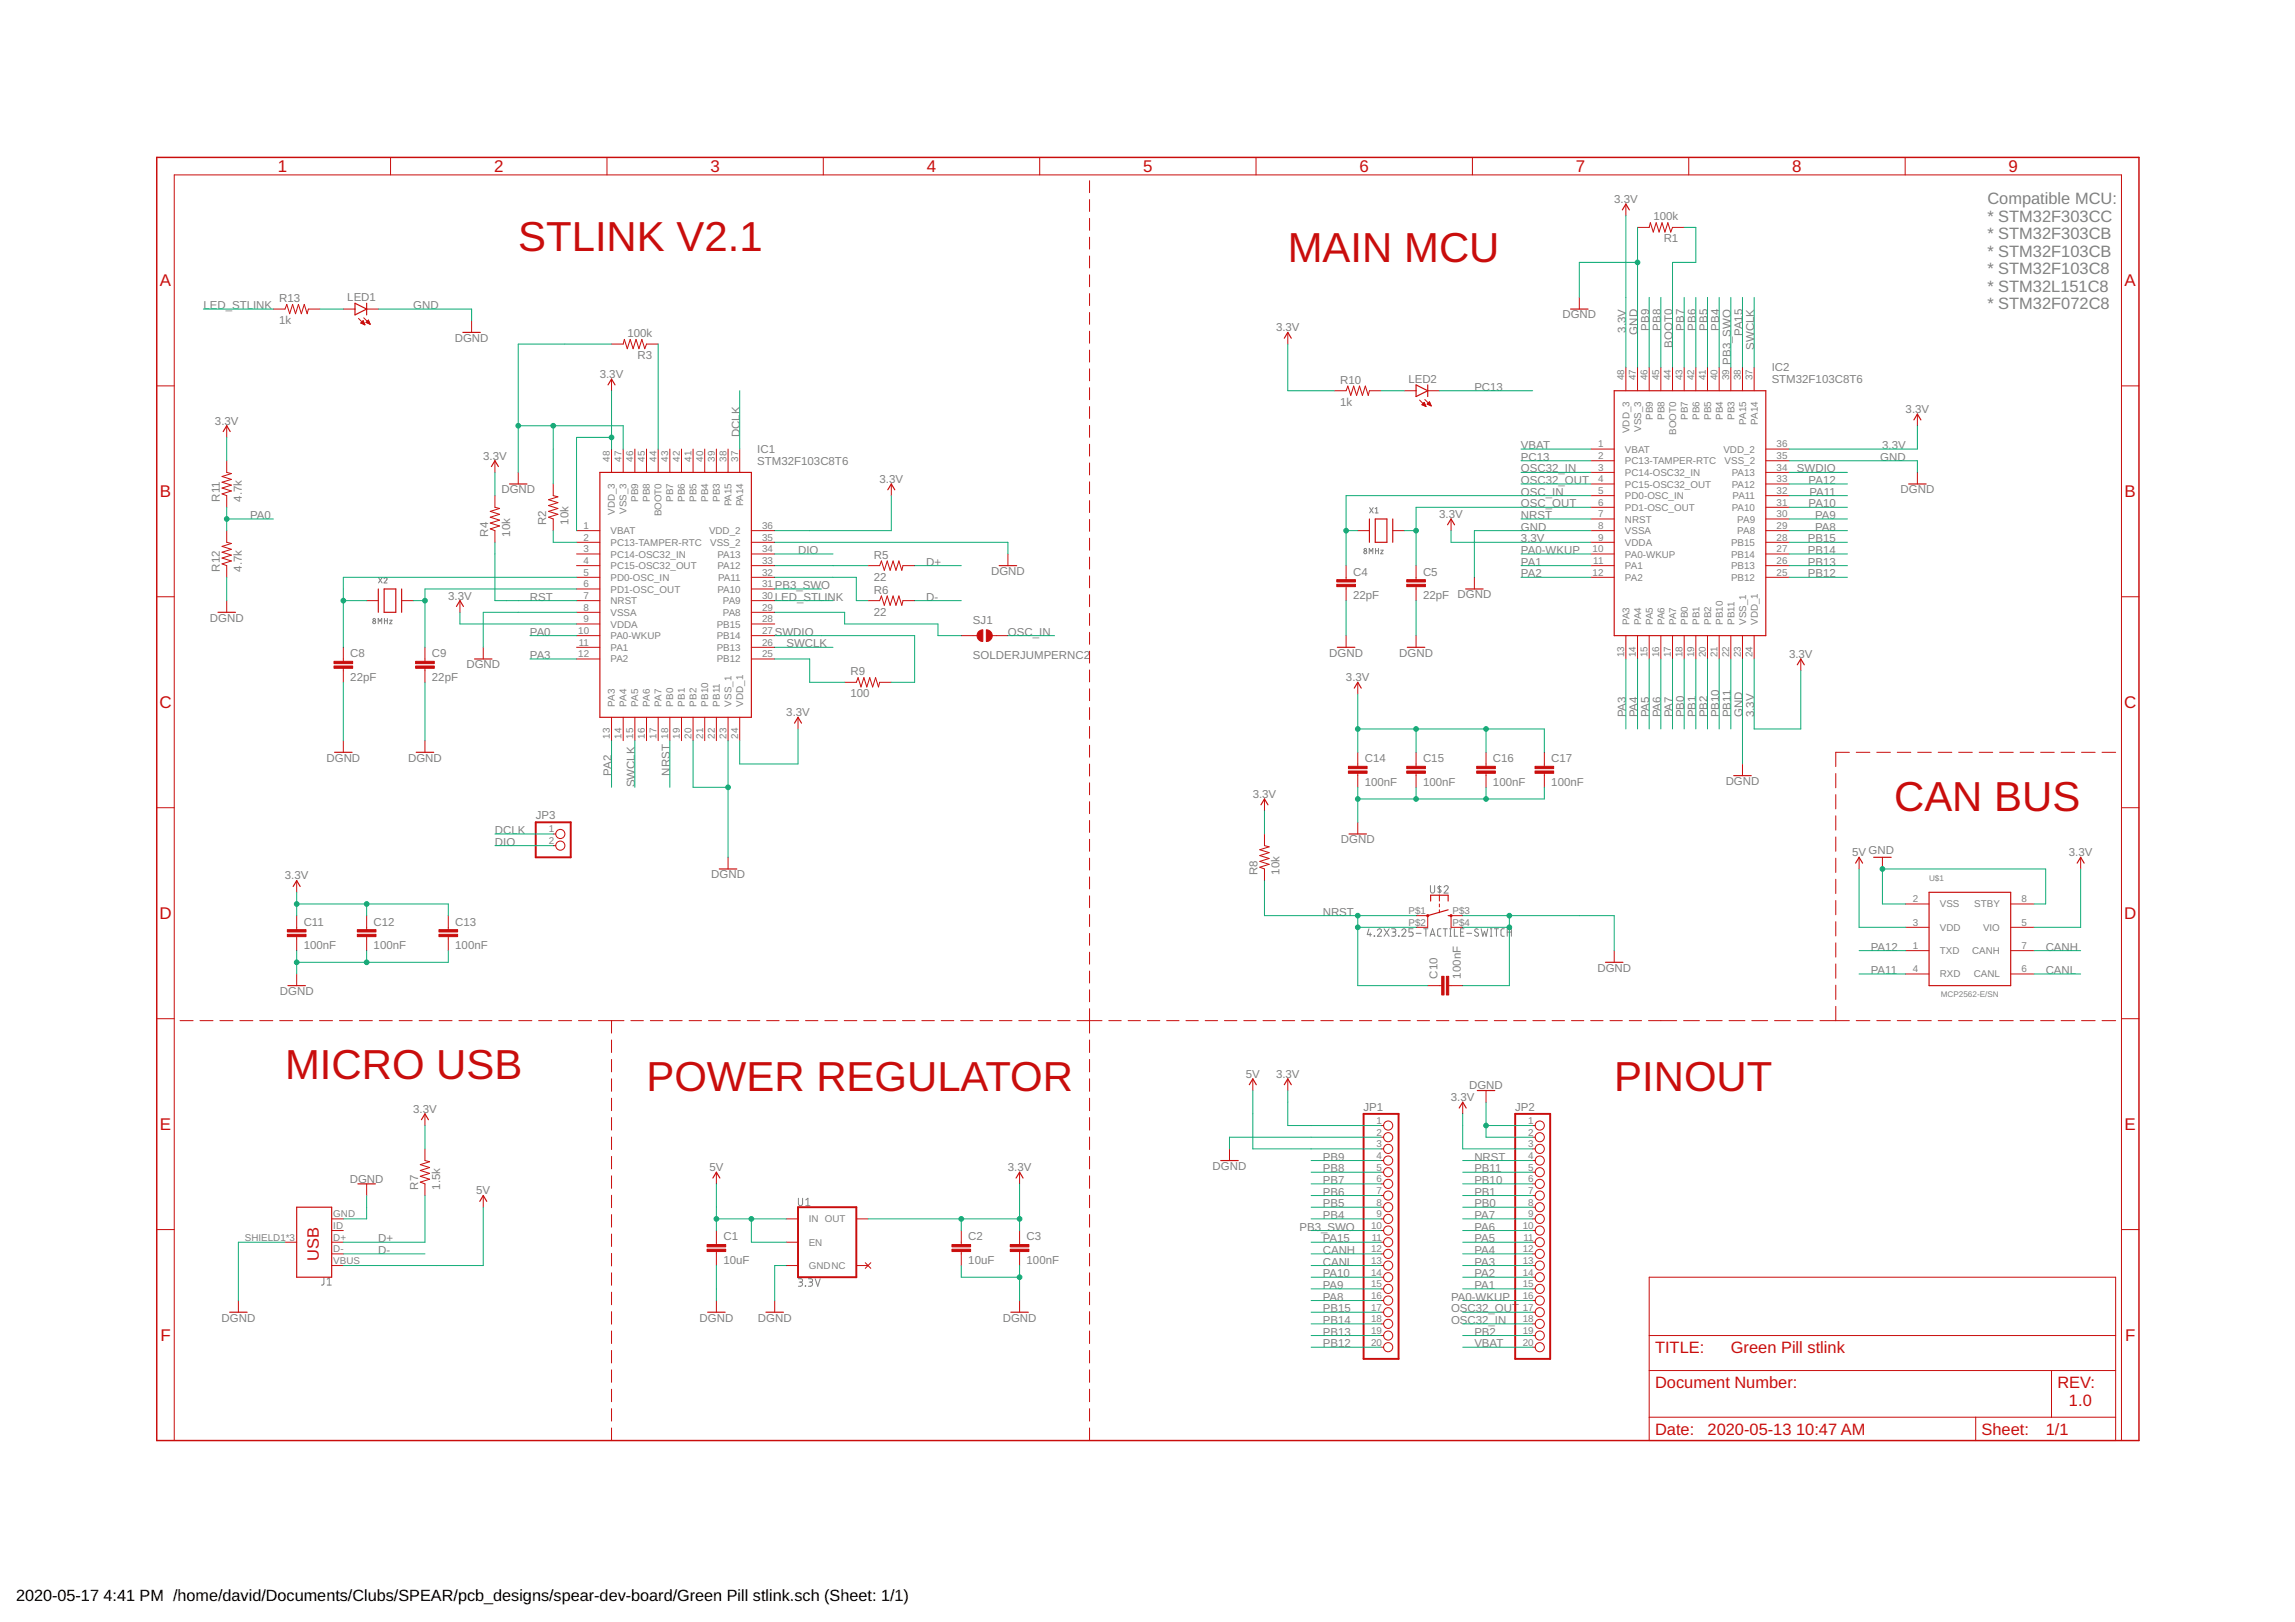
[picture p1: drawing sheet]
<svg xmlns="http://www.w3.org/2000/svg" width="500mm" height="353mm" viewBox="0 0 500 353" stroke-linecap="round" stroke-linejoin="round" font-family="sans-serif">
<defs><g id="words">
<g font-size="9.1" fill="#c90d0c">
<text x="112.9" y="54.6">STLINK V2.1</text>
<text x="280.5" y="57.1">MAIN MCU</text>
<text x="412.6" y="176.5">CAN BUS</text>
<text x="62.1" y="234.9">MICRO USB</text>
<text x="140.8" y="237.4">POWER REGULATOR</text>
<text x="351.6" y="237.4">PINOUT</text>
</g>
<g font-size="3.7" fill="#c90d0c">
<text x="60.5" y="37.5">1</text>
<text x="107.6" y="37.5">2</text>
<text x="154.8" y="37.5">3</text>
<text x="201.9" y="37.5">4</text>
<text x="249" y="37.5">5</text>
<text x="296.1" y="37.5">6</text>
<text x="343.3" y="37.5">7</text>
<text x="390.4" y="37.5">8</text>
<text x="437.5" y="37.5">9</text>
<text x="34.8" y="62.3">A</text>
<text x="462.8" y="62.3">A</text>
<text x="34.8" y="108.3">B</text>
<text x="462.8" y="108.3">B</text>
<text x="34.7" y="154.2">C</text>
<text x="462.7" y="154.2">C</text>
<text x="34.7" y="200.1">D</text>
<text x="462.7" y="200.1">D</text>
<text x="34.8" y="246">E</text>
<text x="462.8" y="246">E</text>
<text x="34.9" y="292">F</text>
<text x="462.9" y="292">F</text>
</g>
<g font-size="3.6" fill="#808080">
<text x="432.9" y="44.4">Compatible MCU:</text>
<text x="432.9" y="48.2">* STM32F303CC</text>
<text x="432.9" y="52">* STM32F303CB</text>
<text x="432.9" y="55.9">* STM32F103CB</text>
<text x="432.9" y="59.7">* STM32F103C8</text>
<text x="432.9" y="63.5">* STM32L151C8</text>
<text x="432.9" y="67.3">* STM32F072C8</text>
</g>
<g font-size="3.6" fill="#c90d0c">
<text x="69.4" y="274.5" transform="rotate(-90 69.4 274.5)">USB</text>
<text x="360.5" y="294.6">TITLE:</text>
<text x="377" y="294.6">Green Pill stlink</text>
<text x="360.5" y="302.2">Document Number:</text>
<text x="448.1" y="302.2">REV:</text>
<text x="450.7" y="306">1.0</text>
<text x="360.5" y="312.4">Date:</text>
<text x="371.9" y="312.4">2020-05-13</text>
<text x="391.2" y="312.4">10:47 AM</text>
<text x="431.6" y="312.4">Sheet:</text>
<text x="445.6" y="312.4">1/1</text>
</g>
<g font-size="3.5">
<text x="3.5" y="348.6">2020-05-17</text>
<text x="22.6" y="348.6">4:41 PM /home/david/Documents/Clubs/SPEAR/pcb_designs/spear-dev-board/Green Pill stlink.sch (Sheet: 1/1)</text>
</g>
<g font-size="2.5" fill="#808080">
<text x="351.6" y="44.2">3.3V</text>
<text x="360.2" y="48">100k</text>
<text x="362.4" y="52.8">R1</text>
<text x="60.8" y="65.8">R13</text>
<text x="75.6" y="65.5">LED1</text>
<text x="44.3" y="67.3">LED_STLINK</text>
<text x="60.8" y="70.6">1k</text>
<text x="90" y="67.3">GND</text>
<text x="340.3" y="69.3">DGND</text>
<text x="99.1" y="74.4">DGND</text>
<text x="136.7" y="73.4">100k</text>
<text x="277.9" y="72.1">3.3V</text>
<text x="354.1" y="72.4" transform="rotate(-90 354.1 72.4)">3.3V</text>
<text x="356.7" y="72.8" transform="rotate(-90 356.7 72.8)">GND</text>
<text x="359.2" y="72" transform="rotate(-90 359.2 72)">PB9</text>
<text x="361.8" y="72" transform="rotate(-90 361.8 72)">PB8</text>
<text x="364.3" y="75.8" transform="rotate(-90 364.3 75.8)">BOOT0</text>
<text x="366.8" y="72" transform="rotate(-90 366.8 72)">PB7</text>
<text x="369.4" y="72" transform="rotate(-90 369.4 72)">PB6</text>
<text x="371.9" y="72" transform="rotate(-90 371.9 72)">PB5</text>
<text x="374.5" y="72" transform="rotate(-90 374.5 72)">PB4</text>
<text x="379.5" y="73.2" transform="rotate(-90 379.5 73.2)">PA15</text>
<text x="382.1" y="76.2" transform="rotate(-90 382.1 76.2)">SWCLK</text>
<text x="130.6" y="82.3">3.3V</text>
<text x="138.9" y="78.2">R3</text>
<text x="291.9" y="83.6">R10</text>
<text x="306.8" y="83.3">LED2</text>
<text x="377" y="79.4" transform="rotate(-90 377 79.4)">PB3_SWO</text>
<text x="385.9" y="83.4">STM32F103C8T6</text>
<text x="385.9" y="80.9">IC2</text>
<text x="291.9" y="88.4">1k</text>
<text x="321.1" y="85.1">PC13</text>
<text x="415.1" y="89.9">3.3V</text>
<text x="46.8" y="92.4">3.3V</text>
<text x="161.1" y="95.2" transform="rotate(-90 161.1 95.2)">DCLK</text>
<text x="105.2" y="100">3.3V</text>
<text x="164.9" y="101.2">STM32F103C8T6</text>
<text x="164.9" y="98.6">IC1</text>
<text x="331.3" y="97.8">VBAT</text>
<text x="331.3" y="100.3">PC13</text>
<text x="409.6" y="100.3">GND</text>
<text x="410" y="97.8">3.3V</text>
<text x="109.2" y="107.4">DGND</text>
<text x="191.6" y="105.1">3.3V</text>
<text x="331.3" y="102.8">OSC32_IN</text>
<text x="331.3" y="105.4">OSC32_OUT</text>
<text x="331.3" y="107.9">OSC_IN</text>
<text x="391.4" y="102.8">SWDIO</text>
<text x="393.9" y="105.4">PA12</text>
<text x="394.1" y="107.9">PA11</text>
<text x="414" y="107.4">DGND</text>
<text x="47.9" y="109.2" transform="rotate(-90 47.9 109.2)">R11</text>
<text x="52.7" y="109.2" transform="rotate(-90 52.7 109.2)">4.7k</text>
<text x="54.5" y="113">PA0</text>
<text x="313.5" y="112.7">3.3V</text>
<text x="331.3" y="110.5">OSC_OUT</text>
<text x="331.3" y="113">NRST</text>
<text x="393.9" y="110.5">PA10</text>
<text x="395.3" y="113">PA9</text>
<text x="106.3" y="116.8" transform="rotate(-90 106.3 116.8)">R4</text>
<text x="111.1" y="116.8" transform="rotate(-90 111.1 116.8)">10k</text>
<text x="119" y="114.3" transform="rotate(-90 119 114.3)">R2</text>
<text x="123.8" y="114.3" transform="rotate(-90 123.8 114.3)">10k</text>
<text x="331.3" y="115.5">GND</text>
<text x="331.3" y="118.1">3.3V</text>
<text x="393.7" y="118.1">PB15</text>
<text x="395.3" y="115.5">PA8</text>
<text x="47.9" y="124.4" transform="rotate(-90 47.9 124.4)">R12</text>
<text x="52.7" y="124.4" transform="rotate(-90 52.7 124.4)">4.7k</text>
<text x="173.8" y="120.6">DIO</text>
<text x="190.3" y="121.7">R5</text>
<text x="201.8" y="123.2">D+</text>
<text x="215.9" y="125.2">DGND</text>
<text x="294.7" y="125.3">C4</text>
<text x="310" y="125.3">C5</text>
<text x="331.3" y="120.6">PA0-WKUP</text>
<text x="331.3" y="123.2">PA1</text>
<text x="331.3" y="125.7">PA2</text>
<text x="393.7" y="120.6">PB14</text>
<text x="393.7" y="123.2">PB13</text>
<text x="393.7" y="125.7">PB12</text>
<text x="97.6" y="130.5">3.3V</text>
<text x="115.4" y="130.8">RST</text>
<text x="168.7" y="128.2">PB3_SWO</text>
<text x="168.7" y="130.8">LED_STLINK</text>
<text x="190.3" y="126.5">22</text>
<text x="190.3" y="129.3">R6</text>
<text x="201.8" y="130.8">D-</text>
<text x="294.7" y="130.4">22pF</text>
<text x="310" y="130.4">22pF</text>
<text x="317.5" y="130.3">DGND</text>
<text x="45.7" y="135.3">DGND</text>
<text x="190.3" y="134.1">22</text>
<text x="211.9" y="135.9">SJ1</text>
<text x="76.3" y="143.1">C8</text>
<text x="94.1" y="143.1">C9</text>
<text x="115.4" y="143.5">PA3</text>
<text x="115.4" y="138.4">PA0</text>
<text x="168.7" y="138.4">SWDIO</text>
<text x="171.3" y="140.9">SWCLK</text>
<text x="211.9" y="143.5">SOLDERJUMPERNC2</text>
<text x="219.5" y="138.4">OSC_IN</text>
<text x="289.5" y="143">DGND</text>
<text x="304.8" y="143">DGND</text>
<text x="389.7" y="143.2">3.3V</text>
<text x="76.3" y="148.2">22pF</text>
<text x="94.1" y="148.2">22pF</text>
<text x="101.6" y="145.5">DGND</text>
<text x="185.3" y="147.1">R9</text>
<text x="293.2" y="148.3">3.3V</text>
<text x="171.3" y="155.9">3.3V</text>
<text x="185.3" y="151.9">100</text>
<text x="354.1" y="156.2" transform="rotate(-90 354.1 156.2)">PA3</text>
<text x="356.7" y="156.2" transform="rotate(-90 356.7 156.2)">PA4</text>
<text x="359.2" y="156.2" transform="rotate(-90 359.2 156.2)">PA5</text>
<text x="361.8" y="156.2" transform="rotate(-90 361.8 156.2)">PA6</text>
<text x="364.3" y="156.2" transform="rotate(-90 364.3 156.2)">PA7</text>
<text x="366.8" y="156.2" transform="rotate(-90 366.8 156.2)">PB0</text>
<text x="369.4" y="156.2" transform="rotate(-90 369.4 156.2)">PB1</text>
<text x="371.9" y="156.2" transform="rotate(-90 371.9 156.2)">PB2</text>
<text x="374.5" y="156.2" transform="rotate(-90 374.5 156.2)">PB10</text>
<text x="377" y="156.2" transform="rotate(-90 377 156.2)">PB11</text>
<text x="379.5" y="156.2" transform="rotate(-90 379.5 156.2)">GND</text>
<text x="382.1" y="156.2" transform="rotate(-90 382.1 156.2)">3.3V</text>
<text x="71.1" y="165.8">DGND</text>
<text x="88.9" y="165.8">DGND</text>
<text x="297.3" y="165.9">C14</text>
<text x="310" y="165.9">C15</text>
<text x="325.2" y="165.9">C16</text>
<text x="337.9" y="165.9">C17</text>
<text x="133.2" y="168.9" transform="rotate(-90 133.2 168.9)">PA2</text>
<text x="138.3" y="171.4" transform="rotate(-90 138.3 171.4)">SWCLK</text>
<text x="145.9" y="168.9" transform="rotate(-90 145.9 168.9)">NRST</text>
<text x="272.9" y="173.7">3.3V</text>
<text x="297.3" y="171">100nF</text>
<text x="310" y="171">100nF</text>
<text x="325.2" y="171">100nF</text>
<text x="337.9" y="171">100nF</text>
<text x="375.9" y="170.9">DGND</text>
<text x="116.7" y="178.4">JP3</text>
<text x="107.8" y="184.1">DIO</text>
<text x="107.8" y="181.6">DCLK</text>
<text x="292.1" y="183.6">DGND</text>
<text x="62.1" y="191.5">3.3V</text>
<text x="154.9" y="191.2">DGND</text>
<text x="273.9" y="190.5" transform="rotate(-90 273.9 190.5)">R8</text>
<text x="278.7" y="190.5" transform="rotate(-90 278.7 190.5)">10k</text>
<text x="403.4" y="186.4">5V GND</text>
<text x="450.6" y="186.4">3.3V</text>
<text x="66.1" y="201.5">C11</text>
<text x="81.4" y="201.5">C12</text>
<text x="99.2" y="201.5">C13</text>
<text x="288.1" y="199.3">NRST</text>
<text x="66.1" y="206.6">100nF</text>
<text x="81.4" y="206.6">100nF</text>
<text x="99.2" y="206.6">100nF</text>
<text x="407.5" y="207">PA12</text>
<text x="445.6" y="207">CANH</text>
<text x="313.1" y="213.1" transform="rotate(-90 313.1 213.1)">C10</text>
<text x="318.2" y="213.1" transform="rotate(-90 318.2 213.1)">100nF</text>
<text x="347.9" y="211.5">DGND</text>
<text x="407.5" y="212">PA11</text>
<text x="445.6" y="212">CANL</text>
<text x="61" y="216.6">DGND</text>
<text x="271.4" y="234.6">5V</text>
<text x="277.9" y="234.6">3.3V</text>
<text x="316" y="239.7">3.3V</text>
<text x="320" y="237.2">DGND</text>
<text x="90" y="242.3">3.3V</text>
<text x="297" y="241.9">JP1</text>
<text x="330" y="241.9">JP2</text>
<text x="76.2" y="257.5">DGND</text>
<text x="154.5" y="255">5V</text>
<text x="219.5" y="255">3.3V</text>
<text x="264.1" y="254.7">DGND</text>
<text x="288.1" y="252.7">PB9</text>
<text x="288.1" y="255.2">PB8</text>
<text x="288.1" y="257.8">PB7</text>
<text x="321.1" y="252.7">NRST</text>
<text x="321.1" y="257.8">PB10</text>
<text x="321.1" y="255.2">PB11</text>
<text x="91.1" y="259" transform="rotate(-90 91.1 259)">R7</text>
<text x="95.9" y="259" transform="rotate(-90 95.9 259)">1.5k</text>
<text x="103.7" y="260">5V</text>
<text x="288.1" y="260.3">PB6</text>
<text x="288.1" y="262.8">PB5</text>
<text x="321.1" y="262.8">PB0</text>
<text x="321.1" y="260.3">PB1</text>
<text x="283" y="267.9">PB3_SWO</text>
<text x="288.1" y="265.4">PB4</text>
<text x="321.1" y="267.9">PA6</text>
<text x="321.1" y="265.4">PA7</text>
<text x="82.4" y="270.5">D+</text>
<text x="82.4" y="273">D-</text>
<text x="157.6" y="275.1">10uF</text>
<text x="157.6" y="270.1">C1</text>
<text x="210.9" y="275.1">10uF</text>
<text x="210.9" y="270.1">C2</text>
<text x="223.6" y="275.1">100nF</text>
<text x="223.6" y="270.1">C3</text>
<text x="288.1" y="270.5">PA15</text>
<text x="288.1" y="273">CANH</text>
<text x="288.1" y="275.5">CANL</text>
<text x="321.1" y="275.5">PA3</text>
<text x="321.1" y="273">PA4</text>
<text x="321.1" y="270.5">PA5</text>
<text x="288.1" y="278.1">PA10</text>
<text x="288.1" y="280.6">PA9</text>
<text x="321.1" y="280.6">PA1</text>
<text x="321.1" y="278.1">PA2</text>
<text x="48.3" y="287.7">DGND</text>
<text x="152.4" y="287.7">DGND</text>
<text x="165.1" y="287.7">DGND</text>
<text x="218.4" y="287.7">DGND</text>
<text x="288.1" y="283.1">PA8</text>
<text x="288.1" y="285.7">PB15</text>
<text x="316.1" y="285.7">OSC32_OUT</text>
<text x="316.1" y="283.1">PA0-WKUP</text>
<text x="288.1" y="288.2">PB14</text>
<text x="288.1" y="290.8">PB13</text>
<text x="288.1" y="293.3">PB12</text>
<text x="316.1" y="288.2">OSC32_IN</text>
<text x="321.1" y="293.3">VBAT</text>
<text x="321.1" y="290.8">PB2</text>
</g>
<g font-size="2.1" fill="#808080">
<text x="353.8" y="82.7" transform="rotate(-90 353.8 82.7)">48</text>
<text x="356.3" y="82.7" transform="rotate(-90 356.3 82.7)">47</text>
<text x="358.9" y="82.7" transform="rotate(-90 358.9 82.7)">46</text>
<text x="361.4" y="82.7" transform="rotate(-90 361.4 82.7)">45</text>
<text x="364" y="82.7" transform="rotate(-90 364 82.7)">44</text>
<text x="366.5" y="82.7" transform="rotate(-90 366.5 82.7)">43</text>
<text x="369" y="82.7" transform="rotate(-90 369 82.7)">42</text>
<text x="371.6" y="82.7" transform="rotate(-90 371.6 82.7)">41</text>
<text x="374.1" y="82.7" transform="rotate(-90 374.1 82.7)">40</text>
<text x="376.7" y="82.7" transform="rotate(-90 376.7 82.7)">39</text>
<text x="379.2" y="82.7" transform="rotate(-90 379.2 82.7)">38</text>
<text x="381.7" y="82.7" transform="rotate(-90 381.7 82.7)">37</text>
<text x="354.9" y="94.3" transform="rotate(-90 354.9 94.3)">VDD_3</text>
<text x="357.5" y="94" transform="rotate(-90 357.5 94)">VSS_3</text>
<text x="360" y="91.4" transform="rotate(-90 360 91.4)">PB9</text>
<text x="362.5" y="91.4" transform="rotate(-90 362.5 91.4)">PB8</text>
<text x="365.1" y="94.6" transform="rotate(-90 365.1 94.6)">BOOT0</text>
<text x="367.6" y="91.4" transform="rotate(-90 367.6 91.4)">PB7</text>
<text x="370.2" y="91.4" transform="rotate(-90 370.2 91.4)">PB6</text>
<text x="372.7" y="91.4" transform="rotate(-90 372.7 91.4)">PB5</text>
<text x="375.2" y="91.4" transform="rotate(-90 375.2 91.4)">PB4</text>
<text x="377.8" y="91.4" transform="rotate(-90 377.8 91.4)">PB3</text>
<text x="380.3" y="92.5" transform="rotate(-90 380.3 92.5)">PA15</text>
<text x="382.8" y="92.5" transform="rotate(-90 382.8 92.5)">PA14</text>
<text x="132.8" y="100.5" transform="rotate(-90 132.8 100.5)">48</text>
<text x="135.4" y="100.5" transform="rotate(-90 135.4 100.5)">47</text>
<text x="137.9" y="100.5" transform="rotate(-90 137.9 100.5)">46</text>
<text x="140.5" y="100.5" transform="rotate(-90 140.5 100.5)">45</text>
<text x="143" y="100.5" transform="rotate(-90 143 100.5)">44</text>
<text x="145.5" y="100.5" transform="rotate(-90 145.5 100.5)">43</text>
<text x="148.1" y="100.5" transform="rotate(-90 148.1 100.5)">42</text>
<text x="150.6" y="100.5" transform="rotate(-90 150.6 100.5)">41</text>
<text x="153.2" y="100.5" transform="rotate(-90 153.2 100.5)">40</text>
<text x="155.7" y="100.5" transform="rotate(-90 155.7 100.5)">39</text>
<text x="158.2" y="100.5" transform="rotate(-90 158.2 100.5)">38</text>
<text x="160.8" y="100.5" transform="rotate(-90 160.8 100.5)">37</text>
<text x="348.1" y="97.4">1</text>
<text x="348.1" y="99.9">2</text>
<text x="353.9" y="98.5">VBAT</text>
<text x="353.9" y="101.1">PC13-TAMPER-RTC</text>
<text x="375.4" y="98.5">VDD_2</text>
<text x="375.6" y="101.1">VSS_2</text>
<text x="387" y="97.4">36</text>
<text x="387" y="99.9">35</text>
<text x="348.1" y="102.5">3</text>
<text x="348.1" y="105">4</text>
<text x="348.1" y="107.6">5</text>
<text x="353.9" y="103.6">PC14-OSC32_IN</text>
<text x="353.9" y="106.1">PC15-OSC32_OUT</text>
<text x="377.2" y="103.6">PA13</text>
<text x="377.2" y="106.1">PA12</text>
<text x="387" y="102.5">34</text>
<text x="387" y="105">33</text>
<text x="387" y="107.6">32</text>
<text x="134" y="112.1" transform="rotate(-90 134 112.1)">VDD_3</text>
<text x="136.5" y="111.8" transform="rotate(-90 136.5 111.8)">VSS_3</text>
<text x="139" y="109.2" transform="rotate(-90 139 109.2)">PB9</text>
<text x="141.6" y="109.2" transform="rotate(-90 141.6 109.2)">PB8</text>
<text x="144.1" y="112.4" transform="rotate(-90 144.1 112.4)">BOOT0</text>
<text x="146.7" y="109.2" transform="rotate(-90 146.7 109.2)">PB7</text>
<text x="149.2" y="109.2" transform="rotate(-90 149.2 109.2)">PB6</text>
<text x="151.7" y="109.2" transform="rotate(-90 151.7 109.2)">PB5</text>
<text x="154.3" y="109.2" transform="rotate(-90 154.3 109.2)">PB4</text>
<text x="156.8" y="109.2" transform="rotate(-90 156.8 109.2)">PB3</text>
<text x="159.4" y="110.3" transform="rotate(-90 159.4 110.3)">PA15</text>
<text x="161.9" y="110.3" transform="rotate(-90 161.9 110.3)">PA14</text>
<text x="348.1" y="110.1">6</text>
<text x="348.1" y="112.6">7</text>
<text x="353.9" y="108.7">PD0-OSC_IN</text>
<text x="353.9" y="111.2">PD1-OSC_OUT</text>
<text x="353.9" y="113.8">NRST</text>
<text x="377.2" y="111.2">PA10</text>
<text x="377.4" y="108.7">PA11</text>
<text x="378.4" y="113.8">PA9</text>
<text x="387" y="110.1">31</text>
<text x="387" y="112.6">30</text>
<text x="127.1" y="115.2">1</text>
<text x="127.1" y="117.7">2</text>
<text x="133" y="116.3">VBAT</text>
<text x="133" y="118.8">PC13-TAMPER-RTC</text>
<text x="154.4" y="116.3">VDD_2</text>
<text x="154.7" y="118.8">VSS_2</text>
<text x="166" y="115.2">36</text>
<text x="166" y="117.7">35</text>
<text x="348.1" y="115.2">8</text>
<text x="348.1" y="117.7">9</text>
<text x="353.9" y="116.3">VSSA</text>
<text x="353.9" y="118.8">VDDA</text>
<text x="377.1" y="118.8">PB15</text>
<text x="378.4" y="116.3">PA8</text>
<text x="387" y="115.2">29</text>
<text x="387" y="117.7">28</text>
<text x="127.1" y="120.3">3</text>
<text x="127.1" y="122.8">4</text>
<text x="127.1" y="125.3">5</text>
<text x="133" y="121.4">PC14-OSC32_IN</text>
<text x="133" y="123.9">PC15-OSC32_OUT</text>
<text x="156.3" y="121.4">PA13</text>
<text x="156.3" y="123.9">PA12</text>
<text x="166" y="120.3">34</text>
<text x="166" y="122.8">33</text>
<text x="166" y="125.3">32</text>
<text x="346.9" y="120.3">10</text>
<text x="346.9" y="125.3">12</text>
<text x="347.1" y="122.8">11</text>
<text x="353.9" y="121.4">PA0-WKUP</text>
<text x="353.9" y="123.9">PA1</text>
<text x="377.1" y="121.4">PB14</text>
<text x="377.1" y="123.9">PB13</text>
<text x="387" y="120.3">27</text>
<text x="387" y="122.8">26</text>
<text x="387" y="125.3">25</text>
<text x="127.1" y="127.9">6</text>
<text x="127.1" y="130.4">7</text>
<text x="133" y="126.5">PD0-OSC_IN</text>
<text x="133" y="129">PD1-OSC_OUT</text>
<text x="133" y="131.5">NRST</text>
<text x="156.3" y="129">PA10</text>
<text x="156.4" y="126.5">PA11</text>
<text x="157.5" y="131.5">PA9</text>
<text x="166" y="127.9">31</text>
<text x="166" y="130.4">30</text>
<text x="353.9" y="126.5">PA2</text>
<text x="377.1" y="126.5">PB12</text>
<text x="127.1" y="133">8</text>
<text x="127.1" y="135.5">9</text>
<text x="133" y="134.1">VSSA</text>
<text x="133" y="136.6">VDDA</text>
<text x="156.1" y="136.6">PB15</text>
<text x="157.5" y="134.1">PA8</text>
<text x="166" y="133">29</text>
<text x="166" y="135.5">28</text>
<text x="354.9" y="136.1" transform="rotate(-90 354.9 136.1)">PA3</text>
<text x="357.5" y="136.1" transform="rotate(-90 357.5 136.1)">PA4</text>
<text x="360" y="136.1" transform="rotate(-90 360 136.1)">PA5</text>
<text x="362.5" y="136.1" transform="rotate(-90 362.5 136.1)">PA6</text>
<text x="365.1" y="136.1" transform="rotate(-90 365.1 136.1)">PA7</text>
<text x="367.6" y="136.1" transform="rotate(-90 367.6 136.1)">PB0</text>
<text x="370.1" y="136.1" transform="rotate(-90 370.1 136.1)">PB1</text>
<text x="372.7" y="136.1" transform="rotate(-90 372.7 136.1)">PB2</text>
<text x="375.2" y="136.1" transform="rotate(-90 375.2 136.1)">PB10</text>
<text x="377.8" y="136.1" transform="rotate(-90 377.8 136.1)">PB11</text>
<text x="380.3" y="136.1" transform="rotate(-90 380.3 136.1)">VSS_1</text>
<text x="382.8" y="136.1" transform="rotate(-90 382.8 136.1)">VDD_1</text>
<text x="125.9" y="138">10</text>
<text x="125.9" y="143.1">12</text>
<text x="126.1" y="140.6">11</text>
<text x="133" y="139.2">PA0-WKUP</text>
<text x="133" y="141.7">PA1</text>
<text x="156.1" y="139.2">PB14</text>
<text x="156.1" y="141.7">PB13</text>
<text x="166" y="138">27</text>
<text x="166" y="140.6">26</text>
<text x="166" y="143.1">25</text>
<text x="353.8" y="143.1" transform="rotate(-90 353.8 143.1)">13</text>
<text x="356.3" y="143.1" transform="rotate(-90 356.3 143.1)">14</text>
<text x="358.9" y="143.1" transform="rotate(-90 358.9 143.1)">15</text>
<text x="361.4" y="143.1" transform="rotate(-90 361.4 143.1)">16</text>
<text x="364" y="143.1" transform="rotate(-90 364 143.1)">17</text>
<text x="366.5" y="143.1" transform="rotate(-90 366.5 143.1)">18</text>
<text x="369" y="143.1" transform="rotate(-90 369 143.1)">19</text>
<text x="371.6" y="143.1" transform="rotate(-90 371.6 143.1)">20</text>
<text x="374.1" y="143.1" transform="rotate(-90 374.1 143.1)">21</text>
<text x="376.7" y="143.1" transform="rotate(-90 376.7 143.1)">22</text>
<text x="379.2" y="143.1" transform="rotate(-90 379.2 143.1)">23</text>
<text x="381.7" y="143.1" transform="rotate(-90 381.7 143.1)">24</text>
<text x="133" y="144.2">PA2</text>
<text x="156.1" y="144.2">PB12</text>
<text x="134" y="153.8" transform="rotate(-90 134 153.8)">PA3</text>
<text x="136.5" y="153.8" transform="rotate(-90 136.5 153.8)">PA4</text>
<text x="139" y="153.8" transform="rotate(-90 139 153.8)">PA5</text>
<text x="141.6" y="153.8" transform="rotate(-90 141.6 153.8)">PA6</text>
<text x="144.1" y="153.8" transform="rotate(-90 144.1 153.8)">PA7</text>
<text x="146.7" y="153.8" transform="rotate(-90 146.7 153.8)">PB0</text>
<text x="149.2" y="153.8" transform="rotate(-90 149.2 153.8)">PB1</text>
<text x="151.7" y="153.8" transform="rotate(-90 151.7 153.8)">PB2</text>
<text x="154.3" y="153.8" transform="rotate(-90 154.3 153.8)">PB10</text>
<text x="156.8" y="153.8" transform="rotate(-90 156.8 153.8)">PB11</text>
<text x="159.4" y="153.8" transform="rotate(-90 159.4 153.8)">VSS_1</text>
<text x="161.9" y="153.8" transform="rotate(-90 161.9 153.8)">VDD_1</text>
<text x="132.8" y="160.9" transform="rotate(-90 132.8 160.9)">13</text>
<text x="135.4" y="160.9" transform="rotate(-90 135.4 160.9)">14</text>
<text x="137.9" y="160.9" transform="rotate(-90 137.9 160.9)">15</text>
<text x="140.5" y="160.9" transform="rotate(-90 140.5 160.9)">16</text>
<text x="143" y="160.9" transform="rotate(-90 143 160.9)">17</text>
<text x="145.5" y="160.9" transform="rotate(-90 145.5 160.9)">18</text>
<text x="148.1" y="160.9" transform="rotate(-90 148.1 160.9)">19</text>
<text x="150.6" y="160.9" transform="rotate(-90 150.6 160.9)">20</text>
<text x="153.2" y="160.9" transform="rotate(-90 153.2 160.9)">21</text>
<text x="155.7" y="160.9" transform="rotate(-90 155.7 160.9)">22</text>
<text x="158.2" y="160.9" transform="rotate(-90 158.2 160.9)">23</text>
<text x="160.8" y="160.9" transform="rotate(-90 160.8 160.9)">24</text>
<text x="119.5" y="181.2">1</text>
<text x="119.5" y="183.7">2</text>
<text x="416.7" y="196.4">2</text>
<text x="422.5" y="197.6">VSS</text>
<text x="430" y="197.6">STBY</text>
<text x="440.3" y="196.4">8</text>
<text x="306.8" y="199">P$1</text>
<text x="306.8" y="201.5">P$2</text>
<text x="316.4" y="199">P$3</text>
<text x="316.4" y="201.5">P$4</text>
<text x="416.7" y="201.5">3</text>
<text x="422.5" y="202.6">VDD</text>
<text x="431.9" y="202.6">VIO</text>
<text x="440.3" y="201.5">5</text>
<text x="416.7" y="206.6">1</text>
<text x="422.5" y="207.7">TXD</text>
<text x="429.6" y="207.7">CANH</text>
<text x="440.3" y="206.6">7</text>
<text x="416.7" y="211.7">4</text>
<text x="422.5" y="212.8">RXD</text>
<text x="429.9" y="212.8">CANL</text>
<text x="440.3" y="211.7">6</text>
<text x="299.8" y="244.7">1</text>
<text x="332.8" y="244.7">1</text>
<text x="299.8" y="247.2">2</text>
<text x="299.8" y="249.8">3</text>
<text x="332.8" y="247.2">2</text>
<text x="332.8" y="249.8">3</text>
<text x="299.8" y="252.3">4</text>
<text x="299.8" y="254.9">5</text>
<text x="299.8" y="257.4">6</text>
<text x="332.8" y="252.3">4</text>
<text x="332.8" y="254.9">5</text>
<text x="332.8" y="257.4">6</text>
<text x="299.8" y="259.9">7</text>
<text x="299.8" y="262.5">8</text>
<text x="332.8" y="259.9">7</text>
<text x="332.8" y="262.5">8</text>
<text x="72.6" y="265">GND</text>
<text x="72.6" y="267.6">ID</text>
<text x="176.2" y="266.1">IN OUT</text>
<text x="298.6" y="267.6">10</text>
<text x="299.8" y="265">9</text>
<text x="331.7" y="267.6">10</text>
<text x="332.8" y="265">9</text>
<text x="53.3" y="270.1">SHIELD1*3</text>
<text x="72.6" y="270.1">D+</text>
<text x="72.6" y="272.6">D-</text>
<text x="72.6" y="275.2">VBUS</text>
<text x="176.2" y="271.2">EN</text>
<text x="298.6" y="272.6">12</text>
<text x="298.6" y="275.2">13</text>
<text x="298.8" y="270.1">11</text>
<text x="331.7" y="272.6">12</text>
<text x="331.7" y="275.2">13</text>
<text x="331.8" y="270.1">11</text>
<text x="176.2" y="276.3">GNDNC</text>
<text x="298.6" y="277.7">14</text>
<text x="298.6" y="280.3">15</text>
<text x="331.7" y="277.7">14</text>
<text x="331.7" y="280.3">15</text>
<text x="298.6" y="282.8">16</text>
<text x="298.6" y="285.3">17</text>
<text x="298.6" y="287.9">18</text>
<text x="331.7" y="282.8">16</text>
<text x="331.7" y="285.3">17</text>
<text x="331.7" y="287.9">18</text>
<text x="298.6" y="290.4">19</text>
<text x="298.6" y="293">20</text>
<text x="331.7" y="290.4">19</text>
<text x="331.7" y="293">20</text>
</g>
<g font-size="1.8" fill="#808080">
<text x="420.2" y="191.7">U$1</text>
<text x="422.7" y="217.1">MCP2562-E/SN</text>
</g>
</g></defs>
<g fill="none" stroke="#808080" stroke-width=".22">
<path d="M298.3 110.5l.8 1.2M299.1 110.5l-.8 1.2M299.5 110.8l.4-.3v1.2M299.5 111.7h.7M299.6 119.4v1.2M299.6 119.9h.6M300.2 119.4v1.2M300.7 119.8h.6l-.6 .8h.6M82.4 135.8v-1.2l.4 .7 .3-.7v1.2M82.4 125.8l.8 1.1M83.2 125.8l-.8 1.1M83.7 126a.32 .32 0 0 1 .4-.2 .32 .32 0 0 1 .1 .5l-.5 .6h.6"/>
<path d="M83.7 134.6v1.2M83.7 135.1h.7M84.4 134.6v1.2M84.9 135h.5l-.5 .8h.5M298.2 120.6v-1.2l.4 .6 .4-.6v1.2M311.6 192.8v1.2a.46 .46 0 0 0 .4 .4 .46 .46 0 0 0 .5-.4v-1.2M313.5 192.8v1.6M313.9 193.1l-.3-.1-.4 .1v.3l.6 .4a.36 .36 0 0 1-.1 .5 .36 .36 0 0 1-.5-.1M314.5 193.2a.45 .45 0 0 1 .7-.4 .45 .45 0 0 1 .1 .7l-.8 .9h.9M298.2 202.2l-.4 1.3h.9M298.4 203.1v.7M299.3 203.8h.1z"/>
<path d="M300 202.6a.44 .44 0 0 1 .6-.4 .44 .44 0 0 1 .2 .7l-.8 .9h.9M301.5 202.2l1.1 1.6M302.6 202.2l-1.1 1.6M303.1 202.2h.6a.36 .36 0 0 1 .3 .4 .36 .36 0 0 1-.3 .3h-.4M303.6 202.9a.46 .46 0 0 1 .4 .5 .46 .46 0 0 1-.4 .4h-.5M304.6 203.8h.1zM305.3 202.6a.44 .44 0 0 1 .7-.4 .44 .44 0 0 1 .1 .7l-.8 .9h.9M307.8 202.2h-.9v.7h.5a.47 .47 0 0 1 .4 .5 .47 .47 0 0 1-.4 .4h-.5M308.5 203.2h1M310.1 202.2h.9M310.6 202.2v1.6M311.5 203.8l.5-1.6 .6 1.6"/>
<path d="M311.6 203.4h.8M313.9 202.2h-.5l-.3 .4 .1 1 .2 .2h.5M314.3 202.2h.9M314.8 202.2v1.6M315.8 203.8h.3M315.8 202.2h.3M315.9 202.2v1.6M316.8 202.2v1.6h.7M318.1 202.9h.6M318.9 202.2h-.8v1.6h.8M319.5 203.2h1M322 202.4l-.2-.2a.37 .37 0 0 0-.5 .2 .37 .37 0 0 0 .1 .5l.5 .3a.38 .38 0 0 1 .1 .5 .38 .38 0 0 1-.5 .1l-.3-.2"/>
<path d="M322.6 202.2l.4 1.6 .3-1 .4 1 .4-1.6M324.6 203.8h.4M324.6 202.2h.4M324.8 202.2v1.6M325.5 202.2h.9M325.9 202.2v1.6M327.7 202.2h-.5l-.3 .4 .1 1 .2 .2h.5M328.3 202.9h.9M328.3 202.2v1.6M329.2 202.2v1.6M70.5 278.2v1.3l-.5 .3M71.3 279.8h.9"/>
<path d="M71.3 278.5l.4-.3v1.6M173.9 278.4h.6a.36 .36 0 0 1 .3 .4 .36 .36 0 0 1-.3 .3h-.4M173.9 260.9v1.1a.46 .46 0 0 0 .5 .5 .46 .46 0 0 0 .4-.5v-1.1M174.3 279.1a.46 .46 0 0 1 .5 .5 .46 .46 0 0 1-.5 .4h-.4M175.4 279.9l.1 .1zM175.5 261.2l.5-.3v1.6M175.5 262.5h.9M176.1 278.4h.5a.36 .36 0 0 1 .4 .4 .36 .36 0 0 1-.4 .3h-.3M176.6 279.1a.46 .46 0 0 1 .4 .5 .46 .46 0 0 1-.4 .4h-.5M177.6 278.4l.5 1.6 .5-1.6"/>
<circle cx="297.4" cy="119.7" r=".26"/>
<circle cx="81.5" cy="134.9" r=".26"/>
<circle cx="81.5" cy="135.5" r=".33"/>
<circle cx="297.4" cy="120.2" r=".33"/>
</g>
<g fill="none" stroke="#c90d0c" stroke-width=".22">
<path d="M85.1 34.3v3.8M132.2 34.3v3.8M179.3 34.3v3.8M226.5 34.3v3.8M237.3 39.3v2.7M273.6 34.3v3.8M320.7 34.3v3.8M367.8 34.3v3.8M415 34.3v3.8M237.3 43.5v2.5M237.3 47.5v2.6M237.3 51.6v2.6"/>
<path d="M237.3 55.7v2.6M237.3 59.8v2.6M354.1 44.4v2.6M356.7 49.5h2.5l.3-1 .6 2 .6-2 .7 2 .6-2 .6 2 .7-2 .6 2 .4-1h2.5M59.5 67.3h2.6l.4-1 .6 2 .6-2 .7 2 .6-2 .6 2 .7-2 .6 2 .3-1h2.5M74.8 67.3h2.5M78.1 69.3l1.4 1.4M78.6 70.3h.7M78.7 70.2h.5M78.8 70.4h.6M78.8 70.1h.4M79 70h.1"/>
<path d="M79.1 69.8h.1M79.1 69.8l-.5 .5 .9 .4M79.1 69.8l.4 .9M79.1 70.5h.3M79.2 69.2l1.4 1.4M79.4 70.7h.1M79.7 70.2h.8M79.7 70.2l.9 .4M79.9 67.3h2.5M79.9 70.1h.5M80 70.3h.5M80 70h.3"/>
<path d="M80.1 69.8h.2M80.2 69.7h.1M80.2 69.7l-.5 .5M80.2 69.7l.4 .9M80.3 70.4h.3M80.6 70.5h.1M102.7 69.8v2.6M133.2 74.9h2.5l.3-1 .6 2 .7-2 .6 2 .6-2 .7 2 .6-2 .6 2 .4-1h2.6M237.3 63.9v2.6M237.3 68v2.6M237.3 72.1v2.6M237.3 76.2v2.6"/>
<path d="M280.5 72.4v2.5M344 64.7v2.6M354.1 80v5.1M356.7 80v5.1M359.2 80v5.1M361.8 80v5.1M364.3 80v5.1M366.8 80v5.1M369.4 80v5.1M371.9 80v5.1M374.5 80v5.1M377 80v5.1"/>
<path d="M379.5 80v5.1M382.1 80v5.1M34.1 84h3.9M49.4 92.7v2.5M133.2 82.5v2.6M133.2 97.8v5M135.7 97.8v5M138.3 97.8v5M140.8 97.8v5M143.4 97.8v5M145.9 97.8v5M148.4 97.8v5"/>
<path d="M151 97.8v5M153.5 97.8v5M156 97.8v5M158.6 97.8v5M161.1 97.8v5M237.3 80.3v2.6M237.3 84.4v2.6M237.3 88.5v2.6M237.3 92.6v2.6M237.3 96.7v2.6M290.7 85.1h2.5l.4-1 .6 2 .7-2 .6 2 .6-2 .7 2 .6-2 .6 2 .3-1h2.5M305.9 85.1h2.5"/>
<path d="M309.2 87.1l1.4 1.4M309.7 88.1l.5-.5 .4 .9zM309.8 88.1h.6M309.8 88.2h.7M309.9 87.9h.4M310 87.8h.3M310.1 88.3h.4M310.1 87.7h.1M310.3 87l1.4 1.4M310.4 88.4h.2M310.9 87.9h.7M311 85.1h2.5"/>
<path d="M311 88.1h.6M311 87.8h.5M311.1 87.7h.3M311.3 87.6h.1M311.3 88.2h.4M311.4 87.5l.3 .9-.8-.4zM311.6 88.3h.1M346.5 97.8h5.1M384.6 97.8h5.1M417.6 90.1v2.6M462.1 84h3.8M49.4 100.3v2.5l1 .3-2 .6 2 .7-2 .6 2 .6-2 .7 2 .6-2 .6 1 .4v2.5"/>
<path d="M49.4 115.5v2.6l1 .2-2 .7 2 .6-2 .6 2 .7-2 .6 2 .6-2 .7 1 .3v2.6M107.8 107.9v2.5l1 .3-2 .6 2 .7-2 .6 2 .6-2 .7 2 .6-2 .6 1 .4v2.6M107.8 100.3v2.5M112.9 102.8v2.6M120.5 105.4v2.5l1 .3-2 .6 2 .6-2 .7 2 .6-2 .6 2 .7-2 .6 1 .4v2.5M125.6 115.5h5.1M125.6 118.1h5.1M163.7 115.5h5M163.7 118.1h5M194.1 105.4v2.5M237.3 100.8v2.6M237.3 104.9v2.6"/>
<path d="M237.3 109v2.6M237.3 113.1v2.6M237.3 117.2v2.6M295.7 115.5h2.6M303.4 115.5h2.5M316.1 113v2.5M346.5 115.5h5.1M346.5 118.1h5.1M346.5 100.3h5.1M346.5 102.8h5.1M346.5 105.4h5.1M346.5 107.9h5.1"/>
<path d="M346.5 110.4h5.1M346.5 113h5.1M384.6 115.5h5.1M384.6 118.1h5.1M384.6 100.3h5.1M384.6 102.8h5.1M384.6 105.4h5.1M384.6 107.9h5.1M384.6 110.4h5.1M384.6 113h5.1M417.6 102.8v2.6M34.1 129.9h3.9"/>
<path d="M49.4 130.8v2.5M79.9 130.8h2.5M87.5 130.8h2.5M100.2 130.8v2.5M125.6 120.6h5.1M125.6 123.1h5.1M125.6 125.7h5.1M125.6 128.2h5.1M125.6 130.8h5.1M125.6 133.3h5.1M125.6 135.8h5.1M125.6 138.4h5.1"/>
<path d="M163.7 120.6h5M163.7 123.1h5M163.7 125.7h5M163.7 128.2h5M163.7 130.8h5M163.7 133.3h5M163.7 135.8h5M163.7 138.4h5M189.1 123.1h2.5l.4-1 .6 2.1 .7-2.1 .6 2.1 .6-2.1 .7 2.1 .6-2.1 .6 2.1 .3-1.1h2.5M189.1 130.8h2.5l.4-1 .6 2 .7-2 .6 2 .6-2 .7 2 .6-2 .6 2 .3-1h2.5M209.4 138.4h3.4M216.1 138.4h3.4"/>
<path d="M219.5 120.6v2.5M237.3 121.3v2.6M237.3 125.4v2.6M237.3 129.5v2.6M237.3 133.6v2.6M237.3 137.7v2.6M293.2 123.1v3.1M293.2 127.7v3.1M293.2 138.4v2.5M308.4 123.1v3.1M308.4 127.7v3.1M308.4 138.4v2.5"/>
<path d="M321.1 125.7v2.5M346.5 120.6h5.1M346.5 123.1h5.1M346.5 125.7h5.1M354.1 138.4v5.1M356.7 138.4v5.1M359.2 138.4v5.1M361.8 138.4v5.1M364.3 138.4v5.1M366.8 138.4v5.1M369.4 138.4v5.1M371.9 138.4v5.1"/>
<path d="M374.5 138.4v5.1M377 138.4v5.1M379.5 138.4v5.1M382.1 138.4v5.1M384.6 120.6h5.1M384.6 123.1h5.1M384.6 125.7h5.1M462.1 129.9h3.8M74.8 140.9v3.1M74.8 145.5v3M92.6 140.9v3.1M92.6 145.5v3"/>
<path d="M105.3 140.9v2.6M125.6 140.9h5.1M125.6 143.5h5.1M133.2 156.2v5M135.7 156.2v5M138.3 156.2v5M140.8 156.2v5M143.4 156.2v5M145.9 156.2v5M148.4 156.2v5M151 156.2v5M153.5 156.2v5"/>
<path d="M156 156.2v5M158.6 156.2v5M161.1 156.2v5M163.7 140.9h5M163.7 143.5h5M173.8 156.2v2.5M184 148.5h2.5l.4-1 .6 2.1 .7-2.1 .6 2.1 .6-2.1 .7 2.1 .6-2.1 .6 2.1 .3-1.1h2.5M237.3 141.8v2.6M237.3 145.9v2.6M237.3 150v2.5M237.3 154.1v2.6M237.3 158.2v2.5"/>
<path d="M295.7 148.5v2.6M392.2 143.5v2.5M34.1 175.9h3.9M74.8 161.2v2.6M92.6 161.2v2.6M237.3 162.2v2.6M237.3 166.3v2.7M237.3 170.4v2.6M237.3 174.5v2.6M237.3 178.6v2.6M275.4 173.9v2.6M295.7 163.8v3"/>
<path d="M295.7 168.4v3M295.7 179v2.6M308.4 163.8v3M308.4 168.4v3M323.7 163.8v3M323.7 168.4v3M336.4 163.8v3M336.4 168.4v3M379.5 166.3v2.6M399.9 168.4v3.1M399.9 173v3.1M399.9 177.6v3.1"/>
<path d="M402.8 163.8h-2.9v3.1M404.3 163.8h3M408.8 163.8h3M413.3 163.8h2.9M417.7 163.8h3M422.2 163.8h2.9M426.6 163.8h3M431.1 163.8h2.9M435.5 163.8h3M440 163.8h3M444.5 163.8h2.9M448.9 163.8h3"/>
<path d="M453.4 163.8h3M457.9 163.8h2.9M462.1 175.9h3.8M64.6 191.7v2.6M64.6 199.3v3.1M79.9 199.3v3.1M97.6 199.3v3.1M120.5 181.6h.6M120.5 184.1h.6M158.6 186.6v2.6M237.3 182.7v2.6M237.3 186.8v2.6"/>
<path d="M237.3 190.9v2.6M237.3 195v2.6M237.3 199.1v2.6M275.4 181.6v2.5l1 .3-2 .6 2 .6-2 .7 2 .6-2 .6 2 .7-2 .6 1 .4v2.5M308.4 199.3h2.6v2.6h-2.6M313.5 194.9v1.3M313.5 196.8v.6M313.5 198.1v.6M318.6 199.3h-2.5v2.6h2.5M399.9 182.2v3.1M399.9 186.8v3.1M399.9 191.4v3.1"/>
<path d="M399.9 196v3.2M404.9 186.6v2.6M410 186.6v2.6M415.1 196.8h5.1M438 196.8h5M453.2 186.6v2.6M64.6 203.9v3.1M64.6 212v2.6M79.9 203.9v3.1M97.6 203.9v3.1M237.3 203.2v2.6M237.3 207.3v2.6"/>
<path d="M237.3 211.4v2.6M237.3 215.5v2.6M237.3 219.6v5.3M311 214.6h3M315.6 214.6h3M351.6 207v2.5M399.9 200.7v3.1M399.9 205.3v3.1M399.9 209.9v3.1M399.9 214.5v3.1M399.9 219.1v3.1M415.1 201.9h5.1"/>
<path d="M415.1 207h5.1M415.1 212h5.1M438 201.9h5M438 207h5M438 212h5M34.1 221.8h3.9M39.2 222.2h2.9M43.6 222.2h2.8M47.9 222.2h2.8M52.2 222.2h2.9M56.6 222.2h2.8M60.9 222.2h2.9"/>
<path d="M65.3 222.2h2.8M69.6 222.2h2.8M73.9 222.2h2.9M78.3 222.2h2.8M82.6 222.2h2.8M87 222.2h2.8M91.3 222.2h2.8M95.6 222.2h2.9M100 222.2h2.8M104.3 222.2h2.8M108.6 222.2h2.9M113 222.2h2.8"/>
<path d="M117.3 222.2h2.9M121.7 222.2h2.8M126 222.2h2.9M130.3 222.2h5.6M133.2 222.2v2.7M133.2 226.4v2.8M133.2 230.7v2.7M133.2 234.9v2.7M133.2 239.1v2.7M137.4 222.2h2.7M141.6 222.2h2.8M145.9 222.2h2.7"/>
<path d="M150.1 222.2h2.7M154.3 222.2h2.7M158.5 222.2h2.8M162.8 222.2h2.7M167 222.2h2.7M171.2 222.2h2.7M175.5 222.2h2.7M179.7 222.2h2.7M183.9 222.2h2.7M188.1 222.2h2.7M192.3 222.2h2.8M196.6 222.2h2.7"/>
<path d="M200.8 222.2h2.7M205 222.2h2.8M209.3 222.2h2.7M213.5 222.2h2.7M217.7 222.2h2.7M221.9 222.2h2.7M226.1 222.2h2.8M230.4 222.2h2.7M234.6 222.2h5.4M237.3 226.4v2.8M237.3 230.7v2.7M237.3 234.9v2.7"/>
<path d="M237.3 239.1v2.7M241.5 222.2h2.7M245.7 222.2h2.7M249.9 222.2h2.7M254.1 222.2h2.7M258.3 222.2h2.7M262.5 222.2h2.7M266.7 222.2h2.7M270.9 222.2h2.7M272.9 234.9v2.5M275.1 222.2h2.7M279.3 222.2h2.7"/>
<path d="M280.5 234.9v2.5M283.5 222.2h2.7M287.7 222.2h2.7M291.9 222.2h2.7M296.1 222.2h2.7M300.3 222.2h2.7M304.5 222.2h2.7M308.7 222.2h2.7M312.9 222.2h2.7M317.1 222.2h2.7M318.6 240v2.5M321.3 222.2h2.7"/>
<path d="M323.7 237.4v2.6M325.5 222.2h2.7M329.7 222.2h2.7M333.9 222.2h2.7M338.1 222.2h2.7M342.3 222.2h2.7M346.5 222.2h2.7M350.7 222.2h2.7M354.9 222.2h2.7M359.1 222.2h6.1M366.7 222.2h3.5M371.7 222.2h3.4"/>
<path d="M376.6 222.2h3.5M381.6 222.2h3.4M386.5 222.2h3.5M391.5 222.2h3.4M396.4 222.2h6.4M404.3 222.2h3M408.8 222.2h3M413.3 222.2h2.9M417.7 222.2h3M422.2 222.2h2.9M426.6 222.2h3M431.1 222.2h2.9"/>
<path d="M435.5 222.2h3M440 222.2h3M444.5 222.2h2.9M448.9 222.2h3M453.4 222.2h3M457.9 222.2h2.9M462.1 221.8h3.8M79.9 257.7v2.6M92.6 242.5v2.5M92.6 250.1v2.6l1 .2-2.1 .7 2.1 .6-2.1 .6 2.1 .7-2.1 .6 2.1 .6-2.1 .7 1.1 .3v2.6M133.2 243.3v2.7M133.2 247.5v2.8"/>
<path d="M133.2 251.8v2.7M133.2 256v2.7M156 255.2v2.5M222.1 255.2v2.5M237.3 243.3v2.7M237.3 247.5v2.8M237.3 251.8v2.7M237.3 256v2.7M267.8 250.1v2.6M300.8 245h.6M300.8 247.6h.6M300.8 250.1h.6"/>
<path d="M300.8 252.7h.6M300.8 255.2h.6M300.8 257.7h.6M333.8 245h.6M333.8 247.6h.6M333.8 250.1h.6M333.8 252.7h.6M333.8 255.2h.6M333.8 257.7h.6M34.1 267.7h3.9M62.1 270.4h2.5M72.2 265.4h2.6"/>
<path d="M72.2 267.9h2.6M72.2 270.4h2.6M72.2 273h2.6M72.2 275.5h2.6M105.3 260.3v2.5M133.2 260.2v2.7M133.2 264.4v2.8M133.2 268.7v2.7M133.2 272.9v2.7M133.2 277.1v2.7M156 267.9v3.1M156 272.5v3"/>
<path d="M171.3 265.4h2.5M171.3 270.4h2.5M171.3 275.5h2.5M186.5 265.4h2.6M186.5 275.5h2.6M188.5 274.9l1.2 1.2M189.7 274.9l-1.2 1.2M209.4 267.9v3.1M209.4 272.5v3M222.1 267.9v3.1M222.1 272.5v3M237.3 260.2v2.7"/>
<path d="M237.3 264.4v2.8M237.3 268.7v2.7M237.3 272.9v2.7M237.3 277.1v2.7M300.8 260.3h.6M300.8 262.8h.6M300.8 265.4h.6M300.8 267.9h.6M300.8 270.4h.6M300.8 273h.6M300.8 275.5h.6M300.8 278.1h.6"/>
<path d="M333.8 260.3h.6M333.8 262.8h.6M333.8 265.4h.6M333.8 267.9h.6M333.8 270.4h.6M333.8 273h.6M333.8 275.5h.6M333.8 278.1h.6M359.2 278.1h101.6v35.5h-101.6zM462.1 267.7h3.8M51.9 283.1v2.6M133.2 281.3v2.8"/>
<path d="M133.2 285.6v2.7M133.2 289.8v2.7M133.2 294v2.7M133.2 298.2v2.7M156 283.1v2.6M168.7 283.1v2.6M222.1 283.1v2.6M237.3 281.3v2.8M237.3 285.6v2.7M237.3 289.8v2.7M237.3 294v2.7M237.3 298.2v2.7"/>
<path d="M300.8 280.6h.6M300.8 283.1h.6M300.8 285.7h.6M300.8 288.2h.6M300.8 290.8h.6M300.8 293.3h.6M333.8 280.6h.6M333.8 283.1h.6M333.8 285.7h.6M333.8 288.2h.6M333.8 290.8h.6M333.8 293.3h.6"/>
<path d="M359.2 290.8h101.6M359.2 298.4h101.6M446.8 298.4v10.1M38 313.6v-275.5h424.1v275.5M133.2 302.5v2.7M133.2 306.7v2.7M133.2 310.9v2.7M237.3 302.5v2.7M237.3 306.7v2.7M237.3 310.9v2.7M359.2 308.5h101.6M430.3 308.5v5.1"/>
<circle cx="122" cy="184.1" r=".99"/>
<circle cx="122" cy="181.6" r=".99"/>
<circle cx="302.4" cy="245" r=".99"/>
<circle cx="302.4" cy="247.6" r=".99"/>
<circle cx="302.4" cy="250.1" r=".99"/>
<circle cx="302.4" cy="252.7" r=".99"/>
<circle cx="302.4" cy="257.7" r=".99"/>
<circle cx="302.4" cy="255.2" r=".99"/>
<circle cx="335.4" cy="255.2" r=".99"/>
<circle cx="335.4" cy="257.7" r=".99"/>
<circle cx="335.4" cy="247.6" r=".99"/>
<circle cx="335.4" cy="250.1" r=".99"/>
<circle cx="335.4" cy="245" r=".99"/>
<circle cx="335.4" cy="252.7" r=".99"/>
<circle cx="302.4" cy="278.1" r=".99"/>
<circle cx="302.4" cy="260.3" r=".99"/>
<circle cx="302.4" cy="262.8" r=".99"/>
<circle cx="302.4" cy="265.4" r=".99"/>
<circle cx="302.4" cy="267.9" r=".99"/>
<circle cx="302.4" cy="270.4" r=".99"/>
<circle cx="302.4" cy="275.5" r=".99"/>
<circle cx="302.4" cy="273" r=".99"/>
<circle cx="335.4" cy="262.8" r=".99"/>
<circle cx="335.4" cy="267.9" r=".99"/>
<circle cx="335.4" cy="260.3" r=".99"/>
<circle cx="335.4" cy="265.4" r=".99"/>
<circle cx="335.4" cy="270.4" r=".99"/>
<circle cx="335.4" cy="273" r=".99"/>
<circle cx="335.4" cy="278.1" r=".99"/>
<circle cx="335.4" cy="275.5" r=".99"/>
<circle cx="302.4" cy="293.3" r=".99"/>
<circle cx="302.4" cy="280.6" r=".99"/>
<circle cx="302.4" cy="283.1" r=".99"/>
<circle cx="302.4" cy="285.7" r=".99"/>
<circle cx="302.4" cy="288.2" r=".99"/>
<circle cx="302.4" cy="290.8" r=".99"/>
<circle cx="335.4" cy="280.6" r=".99"/>
<circle cx="335.4" cy="283.1" r=".99"/>
<circle cx="335.4" cy="288.2" r=".99"/>
<circle cx="335.4" cy="293.3" r=".99"/>
<circle cx="335.4" cy="285.7" r=".99"/>
<circle cx="335.4" cy="290.8" r=".99"/>
</g>
<g fill="none" stroke="#c90d0c" stroke-width=".25">
<path d="M353.4 45.7l.7-1.3 .8 1.3M77.3 66l2.6 1.3-2.6 1.3zM79.9 66v2.6M100.8 72.4h3.8M279.7 73.6l.8-1.2 .8 1.2M342.1 67.3h3.8M48.6 94l.8-1.3 .7 1.3M132.4 83.8l.8-1.3 .8 1.3M308.4 83.8l2.6 1.3-2.6 1.2zM311 83.8v2.5M351.6 85.1h33v53.3h-33zM416.9 91.4l.7-1.3 .8 1.3"/>
<path d="M107 101.6l.8-1.3 .8 1.3M111 105.4h3.8M130.7 102.8h33v53.4h-33zM193.4 106.6l.7-1.2 .8 1.2M298.3 113v5.1M299.6 113h2.5v5.1h-2.5zM303.4 113v5.1M315.3 114.3l.8-1.3 .7 1.3M415.7 105.4h3.8M47.5 133.3h3.8M82.4 128.2v5.1M83.7 128.2h2.5v5.1h-2.5z"/>
<path d="M87.5 128.2v5.1M99.4 132l.8-1.2 .7 1.2M217.6 123.1h3.8M319.2 128.2h3.8M103.4 143.5h3.8M173.1 157.4l.7-1.2 .8 1.2M291.3 140.9h3.8M295 149.8l.7-1.3 .8 1.3M306.5 140.9h3.8M391.5 144.7l.7-1.2 .8 1.2M72.9 163.8h3.8M90.7 163.8h3.8"/>
<path d="M274.7 175.2l.7-1.3 .8 1.3M377.6 168.9h3.8M63.9 193l.7-1.3 .8 1.3M156.7 189.2h3.8M293.8 181.6h3.8M311.6 196.2v-1.3h3.8v1.3M315.4 199.3h.7M315.4 198.1l-4.4 1.2M404.2 187.9l.7-1.3 .8 1.3M408.1 186.6h3.8M420.2 194.3h17.8v20.3h-17.8zM452.4 187.9l.8-1.3 .8 1.3"/>
<path d="M62.7 214.6h3.8M349.7 209.5h3.8M272.1 236.2l.8-1.3 .7 1.3M279.7 236.2l.8-1.3 .8 1.3M321.8 237.4h3.8M78 257.7h3.8M91.8 243.8l.8-1.3 .7 1.3M155.3 256.5l.7-1.3 .8 1.3M221.3 256.5l.8-1.3 .7 1.3M265.9 252.7h3.8M317.8 241.2l.8-1.2 .8 1.2M64.6 262.8h7.6v15.3h-7.6z"/>
<path d="M104.5 261.6l.8-1.3 .7 1.3M50 285.7h3.8M154.1 285.7h3.8M166.8 285.7h3.8M220.2 285.7h3.8"/>
</g>
<g fill="none" stroke="#c90d0c" stroke-width=".42">
<path d="M116.7 179h7.6v7.6h-7.6zM297 242.5h7.6v53.3h-7.6zM330 242.5h7.7v53.3h-7.7zM173.8 262.8h12.7v15.3h-12.7z"/>
<circle cx="311" cy="199.3" r=".13"/>
<circle cx="316.1" cy="199.3" r=".13"/>
</g>
<g fill="#c90d0c" stroke="#c90d0c" stroke-width=".22">
<path d="M154 272h4.1v.5h-4.1z"/>
<path d="M154 271h4.1v.5h-4.1z"/>
<path d="M207.3 272h4.1v.5h-4.1z"/>
<path d="M207.3 271h4.1v.5h-4.1z"/>
<path d="M220 272h4.1v.5h-4.1z"/>
<path d="M220 271h4.1v.5h-4.1z"/>
<path d="M291.2 127.2h4v.5h-4z"/>
<path d="M291.2 126.2h4v.5h-4z"/>
<path d="M306.4 127.2h4.1v.5h-4.1z"/>
<path d="M306.4 126.2h4.1v.5h-4.1z"/>
<path d="M72.7 145h4.1v.5h-4.1z"/>
<path d="M72.7 144h4.1v.5h-4.1z"/>
<path d="M90.5 145h4.1v.5h-4.1z"/>
<path d="M90.5 144h4.1v.5h-4.1z"/>
<path d="M315 212.6h.6v4h-.6z"/>
<path d="M314 212.6h.5v4h-.5z"/>
<path d="M62.6 203.4h4.1v.5h-4.1z"/>
<path d="M62.6 202.4h4.1v.5h-4.1z"/>
<path d="M77.8 203.4h4.1v.5h-4.1z"/>
<path d="M77.8 202.4h4.1v.5h-4.1z"/>
<path d="M95.6 203.4h4.1v.5h-4.1z"/>
<path d="M95.6 202.4h4.1v.5h-4.1z"/>
<path d="M293.7 167.9h4.1v.5h-4.1z"/>
<path d="M293.7 166.8h4.1v.5h-4.1z"/>
<path d="M306.4 167.9h4.1v.5h-4.1z"/>
<path d="M306.4 166.8h4.1v.5h-4.1z"/>
<path d="M321.6 167.9h4.1v.5h-4.1z"/>
<path d="M321.6 166.8h4.1v.5h-4.1z"/>
<path d="M334.3 167.9h4.1v.5h-4.1z"/>
<path d="M334.3 166.8h4.1v.5h-4.1z"/>
</g>
<path d="M34.1 34.3h431.8v279.3h-431.8z" fill="none" stroke="#c90d0c" stroke-width=".32"/>
<g fill="#c90d0c" stroke="#c90d0c" stroke-width=".22">
<path d="M214.8 137.1a1.27 1.27 0 0 1 1.3 1.3 1.27 1.27 0 0 1-1.3 1.3z" fill-rule="evenodd"/>
<path d="M213.1 137.5l1-.4v2.6a1.27 1.27 0 0 1-1.2-.8 1.27 1.27 0 0 1 .2-1.4z" fill-rule="evenodd"/>
</g>
<g fill="none" stroke="#0dab76" stroke-width=".22">
<path d="M354.1 47v33M356.7 49.5v30.5M356.7 57.1h-12.7v7.6M366.8 49.5h2.6v7.6h-5.1v22.9M44.3 67.3h15.2M69.7 67.3h5.1M82.4 67.3h20.3v2.5M133.2 74.9h-20.3v27.9M143.4 74.9v22.9M280.5 74.9v10.2h10.2M359.2 64.7v15.3M361.8 64.7v15.3"/>
<path d="M366.8 64.7v15.3M369.4 64.7v15.3M371.9 64.7v15.3M374.5 64.7v15.3M377 64.7v15.3M379.5 64.7v15.3M382.1 64.7v15.3M49.4 95.2v5.1M112.9 92.7h22.8v5.1M120.5 92.7v12.7M133.2 85.1v12.7M133.2 95.2h-7.6v20.3"/>
<path d="M161.1 85.1v12.7M300.8 85.1h5.1M313.5 85.1h20.3M331.3 97.8h15.2M417.6 92.7v5.1h-27.9M49.4 113h10.1M49.4 110.4v5.1M107.8 102.8v5.1M107.8 118.1v12.7h17.8M120.5 115.5v2.6h5.1M168.7 118.1h50.8v2.5M194.1 107.9v7.6h-25.4"/>
<path d="M293.2 115.5h2.5M305.9 115.5h2.5M316.1 115.5v2.6h30.4M331.3 100.3h15.2M331.3 102.8h15.2M331.3 105.4h15.2M331.3 113h15.2M346.5 107.9h-53.3v15.2M346.5 115.5h-25.4v10.2M346.5 110.4h-38.1v12.7M389.7 100.3h27.9v2.5M389.7 102.8h12.7"/>
<path d="M389.7 105.4h12.7M389.7 107.9h12.7M389.7 115.5h12.7M389.7 110.4h12.7M389.7 113h12.7M389.7 118.1h12.7M49.4 125.7v5.1M74.8 130.8h5.1M90 130.8h2.6M100.2 133.3v2.5h25.4M115.4 138.4h10.2M125.6 125.7h-50.8v15.2"/>
<path d="M125.6 128.2h-33v12.7M125.6 133.3h-20.3v7.6M168.7 138.4h30.5v10.1h-5.1M168.7 133.3h15.3v2.5h20.3v2.6h5.1M168.7 120.6h12.7M168.7 123.1h20.4M168.7 125.7h17.8v5.1h2.6M168.7 128.2h10.2M168.7 130.8h12.7M199.2 123.1h10.2M199.2 130.8h10.2M219.5 138.4h10.2"/>
<path d="M293.2 130.8v7.6M308.4 130.8v7.6M331.3 120.6h15.2M331.3 123.1h15.2M331.3 125.7h15.2M389.7 120.6h12.7M389.7 123.1h12.7M389.7 125.7h12.7M74.8 148.5v12.7M92.6 148.5v12.7M115.4 143.5h10.2M168.7 143.5h7.7v5h7.6"/>
<path d="M168.7 140.9h12.7M173.8 158.7v7.6h-12.7v-5.1M295.7 151.1v12.7M295.7 158.7h40.7v5.1M308.4 158.7v5.1M323.7 158.7v5.1M354.1 143.5v15.2M356.7 143.5v15.2M359.2 143.5v15.2M361.8 143.5v15.2M364.3 143.5v15.2M366.8 143.5v15.2"/>
<path d="M369.4 143.5v15.2M371.9 143.5v15.2M374.5 143.5v15.2M377 143.5v15.2M379.5 143.5v22.8M382.1 143.5v15.2h10.1v-12.7M133.2 161.2v10.2M138.3 161.2v10.2M145.9 161.2v10.2M151 161.2v10.2h7.6M158.6 161.2v25.4M275.4 176.5v5.1"/>
<path d="M295.7 171.4v7.6M308.4 171.4v2.5M323.7 171.4v2.5M336.4 171.4v2.5h-40.7M64.6 194.3v5M64.6 196.8h33v2.5M79.9 196.8v2.5M107.8 184.1h12.7M107.8 181.6h12.7M275.4 191.7v7.6h33M295.7 199.3v15.3h15.3M318.6 199.3h33v7.7"/>
<path d="M328.8 199.3v15.3h-10.2M404.9 189.2v12.7h10.2M415.1 196.8h-5.1v-7.6h35.6v7.6h-2.6M453.2 189.2v12.7h-10.2M64.6 207v5M79.9 207v2.5M97.6 207v2.5h-33M295.7 201.9h12.7M318.6 201.9h10.2M404.9 207h10.2M404.9 212h10.2M443 207h10.2"/>
<path d="M443 212h10.2M272.9 237.4v12.7h27.9M280.5 237.4v7.6h20.3M323.7 240v7.6h10.1M92.6 245v5.1M156 257.7v10.2M222.1 257.7v10.2M285.6 252.7h15.2M285.6 257.7h15.2M285.6 255.2h15.2M300.8 247.6h-33v2.5M318.6 252.7h15.2"/>
<path d="M318.6 257.7h15.2M318.6 255.2h15.2M318.6 242.5v7.6h15.2M323.7 245h10.1M62.1 270.4h-10.2v12.7M74.8 273h17.8M79.9 260.3v5.1h-5.1M92.6 260.3v10.1h-17.8M105.3 262.8v12.7h-30.5M156 265.4h15.3M156 275.5v7.6M163.7 265.4v5h7.6"/>
<path d="M171.3 275.5h-2.6v7.6M189.1 265.4h33M209.4 275.5v2.6h12.7M209.4 265.4v2.5M222.1 275.5v7.6M285.6 278.1h15.2M285.6 275.5h15.2M285.6 273h15.2M285.6 270.4h15.2M285.6 267.9h15.2M285.6 265.4h15.2M285.6 262.8h15.2"/>
<path d="M285.6 260.3h15.2M318.6 278.1h15.2M318.6 275.5h15.2M318.6 273h15.2M318.6 270.4h15.2M318.6 267.9h15.2M318.6 265.4h15.2M318.6 262.8h15.2M318.6 260.3h15.2M285.6 293.3h15.2M285.6 288.2h15.2M285.6 285.7h15.2"/>
<path d="M285.6 283.1h15.2M285.6 280.6h15.2M285.6 290.8h15.2M318.6 293.3h15.2M318.6 288.2h15.2M318.6 285.7h15.2M318.6 283.1h15.2M318.6 280.6h15.2M318.6 290.8h15.2"/>
</g>
<g fill="#0dab76" stroke="#0dab76" stroke-width=".22">
<circle cx="293.2" cy="115.5" r=".51"/>
<circle cx="308.4" cy="115.5" r=".51"/>
<circle cx="295.7" cy="199.3" r=".51"/>
<circle cx="295.7" cy="201.9" r=".51"/>
<circle cx="323.7" cy="245" r=".51"/>
<circle cx="356.7" cy="57.1" r=".51"/>
<circle cx="222.1" cy="278.1" r=".51"/>
<circle cx="112.9" cy="92.7" r=".51"/>
<circle cx="120.5" cy="92.7" r=".51"/>
<circle cx="158.6" cy="171.4" r=".51"/>
<circle cx="328.8" cy="199.3" r=".51"/>
<circle cx="328.8" cy="201.9" r=".51"/>
<circle cx="323.7" cy="173.9" r=".51"/>
<circle cx="308.4" cy="173.9" r=".51"/>
<circle cx="295.7" cy="173.9" r=".51"/>
<circle cx="64.6" cy="209.5" r=".51"/>
<circle cx="79.9" cy="209.5" r=".51"/>
<circle cx="410" cy="189.2" r=".51"/>
<circle cx="209.4" cy="265.4" r=".51"/>
<circle cx="222.1" cy="265.4" r=".51"/>
<circle cx="133.2" cy="95.2" r=".51"/>
<circle cx="323.7" cy="158.7" r=".51"/>
<circle cx="308.4" cy="158.7" r=".51"/>
<circle cx="295.7" cy="158.7" r=".51"/>
<circle cx="64.6" cy="196.8" r=".51"/>
<circle cx="79.9" cy="196.8" r=".51"/>
<circle cx="156" cy="265.4" r=".51"/>
<circle cx="163.7" cy="265.4" r=".51"/>
<circle cx="74.8" cy="130.8" r=".51"/>
<circle cx="92.6" cy="130.8" r=".51"/>
<circle cx="49.4" cy="113" r=".51"/>
</g>
<use href="#words"/>
</svg>
